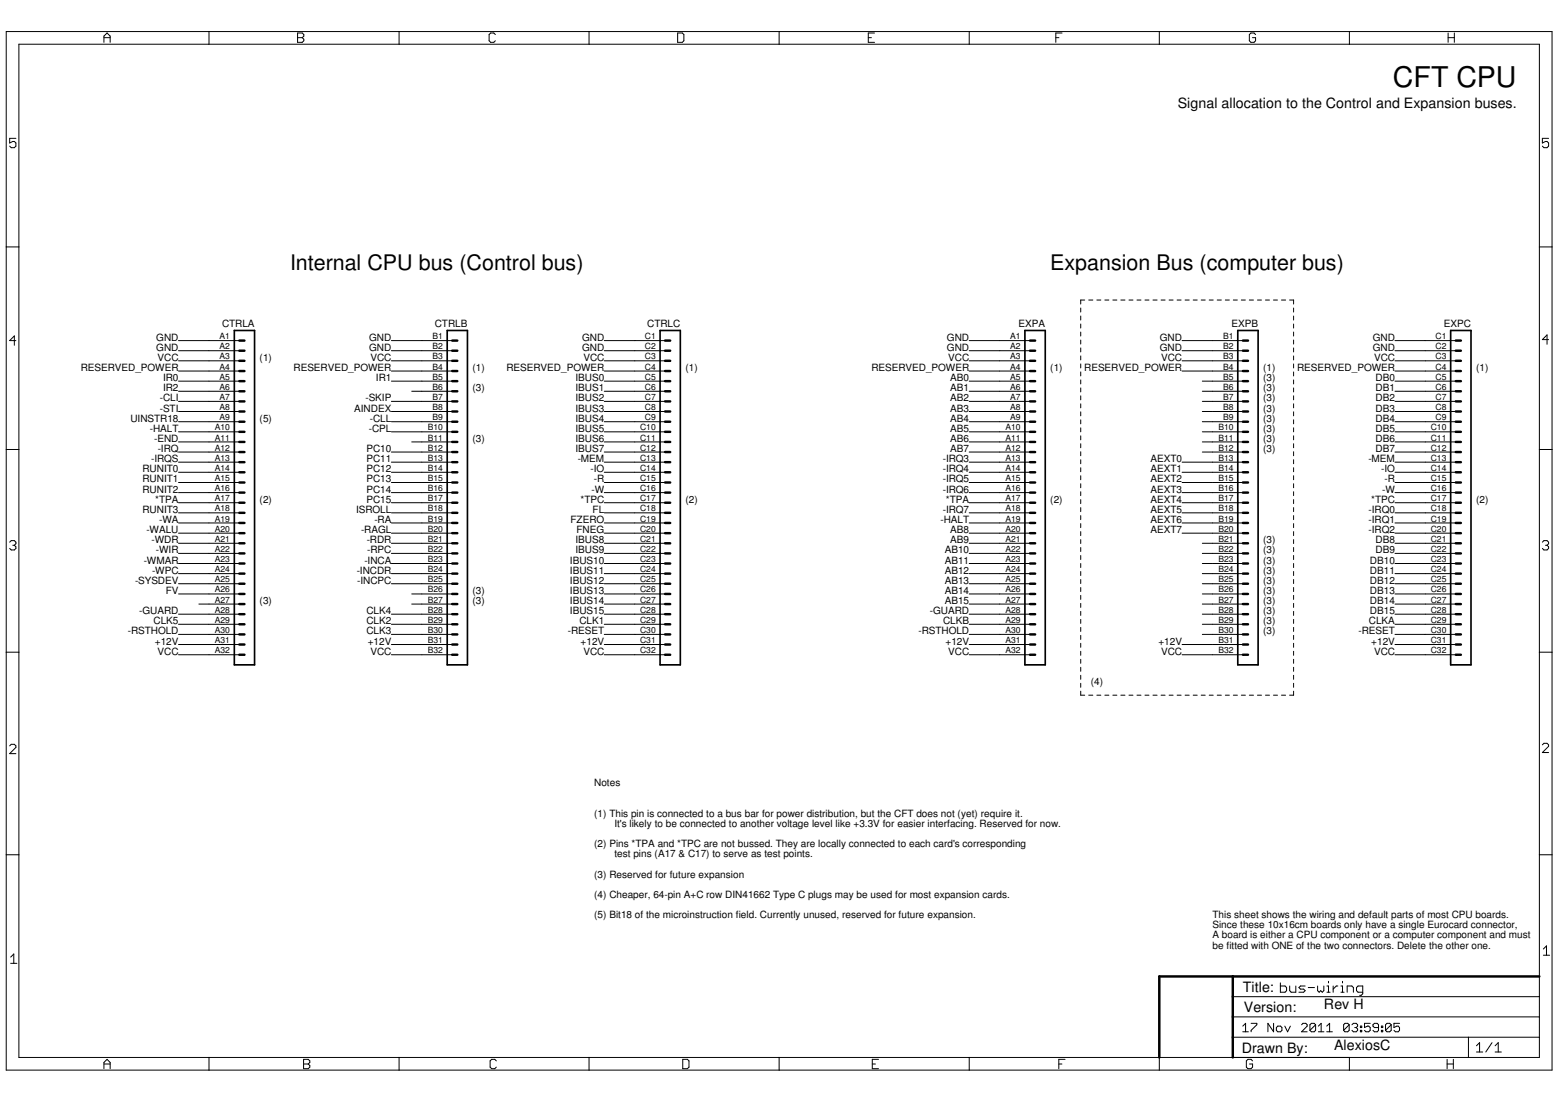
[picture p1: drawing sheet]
<svg xmlns="http://www.w3.org/2000/svg" width="297mm" height="210mm" viewBox="0 0 297 210" stroke-linecap="round" stroke-linejoin="round" font-family="sans-serif">
<defs><g id="words">
<text font-size="5.4" x="265.2" y="16.6">CFT CPU</text>
<g font-size="4.1">
<text x="55.2" y="51.4">Internal CPU bus (Control bus)</text>
<text x="200" y="51.4">Expansion Bus (computer bus)</text>
</g>
<g font-size="2.7">
<text x="224.3" y="20.5">Signal allocation to the Control and Expansion buses.</text>
<text x="236.7" y="189">Title:</text>
<text x="236.9" y="192.8">Version:</text>
<text x="252.1" y="192.3">Rev H</text>
<text x="236.5" y="200.6">Drawn By:</text>
<text x="254" y="200">AlexiosC</text>
</g>
<g font-size="1.9">
<text x="29.8" y="64.9">GND</text>
<text x="42.3" y="62.4">CTRLA</text>
<text x="70.3" y="64.9">GND</text>
<text x="82.8" y="62.4">CTRLB</text>
<text x="110.8" y="64.9">GND</text>
<text x="123.3" y="62.4">CTRLC</text>
<text x="180.3" y="64.9">GND</text>
<text x="193.9" y="62.4">EXPA</text>
<text x="220.8" y="64.9">GND</text>
<text x="234.5" y="62.4">EXPB</text>
<text x="261.4" y="64.9">GND</text>
<text x="274.9" y="62.4">EXPC</text>
<text x="15.4" y="70.7">RESERVED_POWER</text>
<text x="29.8" y="66.8">GND</text>
<text x="30" y="68.7">VCC</text>
<text x="49.4" y="68.7">(1)</text>
<text x="55.9" y="70.7">RESERVED_POWER</text>
<text x="70.3" y="66.8">GND</text>
<text x="70.6" y="68.7">VCC</text>
<text x="90" y="70.7">(1)</text>
<text x="96.4" y="70.7">RESERVED_POWER</text>
<text x="110.8" y="66.8">GND</text>
<text x="111.1" y="68.7">VCC</text>
<text x="130.5" y="70.7">(1)</text>
<text x="165.9" y="70.7">RESERVED_POWER</text>
<text x="180.3" y="66.8">GND</text>
<text x="180.6" y="68.7">VCC</text>
<text x="200" y="70.7">(1)</text>
<text x="206.5" y="70.7">RESERVED_POWER</text>
<text x="220.8" y="66.8">GND</text>
<text x="221.1" y="68.7">VCC</text>
<text x="240.5" y="70.7">(1)</text>
<text x="247" y="70.7">RESERVED_POWER</text>
<text x="261.4" y="66.8">GND</text>
<text x="261.6" y="68.7">VCC</text>
<text x="281.1" y="70.7">(1)</text>
<text x="30.4" y="76.5">-CLI</text>
<text x="31.1" y="72.6">IR0</text>
<text x="31.1" y="74.5">IR2</text>
<text x="69.6" y="76.5">-SKIP</text>
<text x="71.6" y="72.6">IR1</text>
<text x="90" y="74.5">(3)</text>
<text x="109.6" y="72.6">IBUS0</text>
<text x="109.6" y="74.5">IBUS1</text>
<text x="109.6" y="76.5">IBUS2</text>
<text x="180.9" y="76.5">AB2</text>
<text x="180.9" y="74.5">AB1</text>
<text x="180.9" y="72.6">AB0</text>
<text x="240.5" y="72.6">(3)</text>
<text x="240.5" y="74.5">(3)</text>
<text x="240.5" y="76.5">(3)</text>
<text x="261.9" y="76.5">DB2</text>
<text x="261.9" y="74.5">DB1</text>
<text x="261.9" y="72.6">DB0</text>
<text x="24.8" y="80.3">UINSTR18</text>
<text x="28.5" y="82.2">-HALT</text>
<text x="30.4" y="78.4">-STI</text>
<text x="49.4" y="80.3">(5)</text>
<text x="67.4" y="78.4">AINDEX</text>
<text x="70.2" y="82.2">-CPL</text>
<text x="70.4" y="80.3">-CLL</text>
<text x="109.6" y="78.4">IBUS3</text>
<text x="109.6" y="80.3">IBUS4</text>
<text x="109.6" y="82.2">IBUS5</text>
<text x="180.9" y="82.2">AB5</text>
<text x="180.9" y="80.3">AB4</text>
<text x="180.9" y="78.4">AB3</text>
<text x="240.5" y="78.4">(3)</text>
<text x="240.5" y="80.3">(3)</text>
<text x="240.5" y="82.2">(3)</text>
<text x="261.9" y="82.2">DB5</text>
<text x="261.9" y="80.3">DB4</text>
<text x="261.9" y="78.4">DB3</text>
<text x="27.1" y="90">RUNIT0</text>
<text x="28.8" y="88">-IRQS</text>
<text x="29.4" y="84.2">-END</text>
<text x="30" y="86.1">-IRQ</text>
<text x="69.8" y="86.1">PC10</text>
<text x="69.8" y="88">PC11</text>
<text x="69.8" y="90">PC12</text>
<text x="90" y="84.2">(3)</text>
<text x="109.6" y="84.2">IBUS6</text>
<text x="109.6" y="86.1">IBUS7</text>
<text x="110" y="88">-MEM</text>
<text x="112.5" y="90">-IO</text>
<text x="179.5" y="88">-IRQ3</text>
<text x="179.5" y="90">-IRQ4</text>
<text x="180.9" y="86.1">AB7</text>
<text x="180.9" y="84.2">AB6</text>
<text x="219" y="90">AEXT1</text>
<text x="219" y="88">AEXT0</text>
<text x="240.5" y="84.2">(3)</text>
<text x="240.5" y="86.1">(3)</text>
<text x="260.6" y="88">-MEM</text>
<text x="261.9" y="86.1">DB7</text>
<text x="261.9" y="84.2">DB6</text>
<text x="263" y="90">-IO</text>
<text x="27.1" y="91.9">RUNIT1</text>
<text x="27.1" y="93.8">RUNIT2</text>
<text x="29.6" y="95.8">*TPA</text>
<text x="49.4" y="95.8">(2)</text>
<text x="69.8" y="91.9">PC13</text>
<text x="69.8" y="93.8">PC14</text>
<text x="69.8" y="95.8">PC15</text>
<text x="110.5" y="95.8">*TPC</text>
<text x="112.7" y="93.8">-W</text>
<text x="113.1" y="91.9">-R</text>
<text x="130.5" y="95.8">(2)</text>
<text x="179.5" y="91.9">-IRQ5</text>
<text x="179.5" y="93.8">-IRQ6</text>
<text x="180.1" y="95.8">*TPA</text>
<text x="200" y="95.8">(2)</text>
<text x="219" y="95.8">AEXT4</text>
<text x="219" y="93.8">AEXT3</text>
<text x="219" y="91.9">AEXT2</text>
<text x="261.1" y="95.8">*TPC</text>
<text x="263.2" y="93.8">-W</text>
<text x="263.6" y="91.9">-R</text>
<text x="281.1" y="95.8">(2)</text>
<text x="27.1" y="97.7">RUNIT3</text>
<text x="27.9" y="101.5">-WALU</text>
<text x="30.3" y="99.6">-WA</text>
<text x="67.8" y="97.7">ISROLL</text>
<text x="68.8" y="101.5">-RAGL</text>
<text x="71.3" y="99.6">-RA</text>
<text x="108.6" y="99.6">FZERO</text>
<text x="109.8" y="101.5">FNEG</text>
<text x="112.8" y="97.7">FL</text>
<text x="179.1" y="99.6">-HALT</text>
<text x="179.5" y="97.7">-IRQ7</text>
<text x="180.9" y="101.5">AB8</text>
<text x="219" y="101.5">AEXT7</text>
<text x="219" y="99.6">AEXT6</text>
<text x="219" y="97.7">AEXT5</text>
<text x="260.6" y="97.7">-IRQ0</text>
<text x="260.6" y="101.5">-IRQ2</text>
<text x="260.6" y="99.6">-IRQ1</text>
<text x="27.4" y="107.3">-WMAR</text>
<text x="28.9" y="103.5">-WDR</text>
<text x="29.7" y="105.4">-WIR</text>
<text x="69.4" y="107.3">-INCA</text>
<text x="69.8" y="103.5">-RDR</text>
<text x="69.9" y="105.4">-RPC</text>
<text x="108.5" y="107.3">IBUS10</text>
<text x="109.6" y="105.4">IBUS9</text>
<text x="109.6" y="103.5">IBUS8</text>
<text x="179.9" y="107.3">AB11</text>
<text x="179.9" y="105.4">AB10</text>
<text x="180.9" y="103.5">AB9</text>
<text x="240.5" y="103.5">(3)</text>
<text x="240.5" y="105.4">(3)</text>
<text x="240.5" y="107.3">(3)</text>
<text x="260.8" y="107.3">DB10</text>
<text x="261.9" y="105.4">DB9</text>
<text x="261.9" y="103.5">DB8</text>
<text x="25.7" y="111.2">-SYSDEV</text>
<text x="29" y="109.3">-WPC</text>
<text x="31.6" y="113.1">FV</text>
<text x="67.9" y="109.3">-INCDR</text>
<text x="68" y="111.2">-INCPC</text>
<text x="90" y="113.1">(3)</text>
<text x="108.5" y="113.1">IBUS13</text>
<text x="108.5" y="111.2">IBUS12</text>
<text x="108.5" y="109.3">IBUS11</text>
<text x="179.9" y="113.1">AB14</text>
<text x="179.9" y="111.2">AB13</text>
<text x="179.9" y="109.3">AB12</text>
<text x="240.5" y="109.3">(3)</text>
<text x="240.5" y="111.2">(3)</text>
<text x="240.5" y="113.1">(3)</text>
<text x="260.8" y="113.1">DB13</text>
<text x="260.8" y="111.2">DB12</text>
<text x="260.8" y="109.3">DB11</text>
<text x="26.5" y="117">-GUARD</text>
<text x="29.3" y="118.9">CLK5</text>
<text x="49.4" y="115.1">(3)</text>
<text x="69.8" y="118.9">CLK2</text>
<text x="69.8" y="117">CLK4</text>
<text x="90" y="115.1">(3)</text>
<text x="108.5" y="117">IBUS15</text>
<text x="108.5" y="115.1">IBUS14</text>
<text x="110.3" y="118.9">CLK1</text>
<text x="177.1" y="117">-GUARD</text>
<text x="179.6" y="118.9">CLKB</text>
<text x="179.9" y="115.1">AB15</text>
<text x="240.5" y="115.1">(3)</text>
<text x="240.5" y="117">(3)</text>
<text x="240.5" y="118.9">(3)</text>
<text x="260.7" y="118.9">CLKA</text>
<text x="260.8" y="117">DB15</text>
<text x="260.8" y="115.1">DB14</text>
<text x="24.4" y="120.8">-RSTHOLD</text>
<text x="29.5" y="122.8">+12V</text>
<text x="30" y="124.7">VCC</text>
<text x="69.8" y="120.8">CLK3</text>
<text x="70" y="122.8">+12V</text>
<text x="70.6" y="124.7">VCC</text>
<text x="108.1" y="120.8">-RESET</text>
<text x="110.6" y="122.8">+12V</text>
<text x="111.1" y="124.7">VCC</text>
<text x="174.9" y="120.8">-RSTHOLD</text>
<text x="180" y="122.8">+12V</text>
<text x="180.6" y="124.7">VCC</text>
<text x="220.6" y="122.8">+12V</text>
<text x="221.1" y="124.7">VCC</text>
<text x="240.5" y="120.8">(3)</text>
<text x="258.7" y="120.8">-RESET</text>
<text x="261.1" y="122.8">+12V</text>
<text x="261.6" y="124.7">VCC</text>
<text x="207.7" y="130.5">(4)</text>
<text x="113.1" y="149.8">Notes</text>
<text x="113.1" y="155.6">(1) This pin is connected to a bus bar for power distribution, but the CFT does not (yet) require it.</text>
<text x="113.1" y="161.4">(2) Pins *TPA and *TPC are not bussed. They are locally connected to each card's corresponding</text>
<text x="117" y="157.5">It's likely to be connected to another voltage level like +3.3V for easier interfacing. Reserved for now.</text>
<text x="113.1" y="167.2">(3) Reserved for future expansion</text>
<text x="117" y="163.3">test pins (A17 &amp; C17) to serve as test points.</text>
<text x="113.1" y="171">(4) Cheaper, 64-pin A+C row DIN41662 Type C plugs may be used for most expansion cards.</text>
<text x="113.1" y="174.9">(5) Bit18 of the microinstruction field. Currently unused, reserved for future expansion.</text>
<text x="230.9" y="174.9">This sheet shows the wiring and default parts of most CPU boards.</text>
<text x="230.9" y="176.8">Since these 10x16cm boards only have a single Eurocard connector,</text>
<text x="230.9" y="178.7">A board is either a CPU component or a computer component and must</text>
<text x="230.9" y="180.7">be fitted with ONE of the two connectors. Delete the other one.</text>
</g>
<g font-size="1.6">
<text x="41.8" y="64.6">A1</text>
<text x="82.3" y="64.6">B1</text>
<text x="122.8" y="64.6">C1</text>
<text x="192.4" y="64.6">A1</text>
<text x="232.9" y="64.6">B1</text>
<text x="273.3" y="64.6">C1</text>
<text x="41.8" y="66.5">A2</text>
<text x="41.8" y="68.5">A3</text>
<text x="41.8" y="70.4">A4</text>
<text x="82.3" y="66.5">B2</text>
<text x="82.3" y="68.5">B3</text>
<text x="82.3" y="70.4">B4</text>
<text x="122.8" y="66.5">C2</text>
<text x="122.8" y="68.5">C3</text>
<text x="122.8" y="70.4">C4</text>
<text x="192.4" y="66.5">A2</text>
<text x="192.4" y="68.5">A3</text>
<text x="192.4" y="70.4">A4</text>
<text x="232.9" y="66.5">B2</text>
<text x="232.9" y="68.5">B3</text>
<text x="232.9" y="70.4">B4</text>
<text x="273.3" y="66.5">C2</text>
<text x="273.3" y="68.5">C3</text>
<text x="273.3" y="70.4">C4</text>
<text x="41.8" y="72.3">A5</text>
<text x="41.8" y="74.3">A6</text>
<text x="41.8" y="76.2">A7</text>
<text x="82.3" y="72.3">B5</text>
<text x="82.3" y="74.3">B6</text>
<text x="82.3" y="76.2">B7</text>
<text x="122.8" y="72.3">C5</text>
<text x="122.8" y="74.3">C6</text>
<text x="122.8" y="76.2">C7</text>
<text x="192.4" y="72.3">A5</text>
<text x="192.4" y="74.3">A6</text>
<text x="192.4" y="76.2">A7</text>
<text x="232.9" y="72.3">B5</text>
<text x="232.9" y="74.3">B6</text>
<text x="232.9" y="76.2">B7</text>
<text x="273.3" y="72.3">C5</text>
<text x="273.3" y="74.3">C6</text>
<text x="273.3" y="76.2">C7</text>
<text x="40.9" y="82">A10</text>
<text x="40.9" y="83.9">A11</text>
<text x="41.8" y="78.1">A8</text>
<text x="41.8" y="80">A9</text>
<text x="81.4" y="82">B10</text>
<text x="81.4" y="83.9">B11</text>
<text x="82.3" y="78.1">B8</text>
<text x="82.3" y="80">B9</text>
<text x="121.9" y="82">C10</text>
<text x="121.9" y="83.9">C11</text>
<text x="122.8" y="78.1">C8</text>
<text x="122.8" y="80">C9</text>
<text x="191.5" y="82">A10</text>
<text x="191.5" y="83.9">A11</text>
<text x="192.4" y="78.1">A8</text>
<text x="192.4" y="80">A9</text>
<text x="232" y="82">B10</text>
<text x="232" y="83.9">B11</text>
<text x="232.9" y="78.1">B8</text>
<text x="232.9" y="80">B9</text>
<text x="272.4" y="82">C10</text>
<text x="272.4" y="83.9">C11</text>
<text x="273.3" y="78.1">C8</text>
<text x="273.3" y="80">C9</text>
<text x="40.9" y="85.8">A12</text>
<text x="40.9" y="87.8">A13</text>
<text x="40.9" y="89.7">A14</text>
<text x="81.4" y="85.8">B12</text>
<text x="81.4" y="87.8">B13</text>
<text x="81.4" y="89.7">B14</text>
<text x="121.9" y="85.8">C12</text>
<text x="121.9" y="87.8">C13</text>
<text x="121.9" y="89.7">C14</text>
<text x="191.5" y="85.8">A12</text>
<text x="191.5" y="87.8">A13</text>
<text x="191.5" y="89.7">A14</text>
<text x="232" y="85.8">B12</text>
<text x="232" y="87.8">B13</text>
<text x="232" y="89.7">B14</text>
<text x="272.4" y="85.8">C12</text>
<text x="272.4" y="87.8">C13</text>
<text x="272.4" y="89.7">C14</text>
<text x="40.9" y="91.6">A15</text>
<text x="40.9" y="93.6">A16</text>
<text x="40.9" y="95.5">A17</text>
<text x="81.4" y="91.6">B15</text>
<text x="81.4" y="93.6">B16</text>
<text x="81.4" y="95.5">B17</text>
<text x="121.9" y="91.6">C15</text>
<text x="121.9" y="93.6">C16</text>
<text x="121.9" y="95.5">C17</text>
<text x="191.5" y="91.6">A15</text>
<text x="191.5" y="93.6">A16</text>
<text x="191.5" y="95.5">A17</text>
<text x="232" y="91.6">B15</text>
<text x="232" y="93.6">B16</text>
<text x="232" y="95.5">B17</text>
<text x="272.4" y="91.6">C15</text>
<text x="272.4" y="93.6">C16</text>
<text x="272.4" y="95.5">C17</text>
<text x="40.9" y="97.4">A18</text>
<text x="40.9" y="99.3">A19</text>
<text x="40.9" y="101.3">A20</text>
<text x="81.4" y="97.4">B18</text>
<text x="81.4" y="99.3">B19</text>
<text x="81.4" y="101.3">B20</text>
<text x="121.9" y="97.4">C18</text>
<text x="121.9" y="99.3">C19</text>
<text x="121.9" y="101.3">C20</text>
<text x="191.5" y="97.4">A18</text>
<text x="191.5" y="99.3">A19</text>
<text x="191.5" y="101.3">A20</text>
<text x="232" y="97.4">B18</text>
<text x="232" y="99.3">B19</text>
<text x="232" y="101.3">B20</text>
<text x="272.4" y="97.4">C18</text>
<text x="272.4" y="99.3">C19</text>
<text x="272.4" y="101.3">C20</text>
<text x="40.9" y="103.2">A21</text>
<text x="40.9" y="105.1">A22</text>
<text x="40.9" y="107.1">A23</text>
<text x="81.4" y="103.2">B21</text>
<text x="81.4" y="105.1">B22</text>
<text x="81.4" y="107.1">B23</text>
<text x="121.9" y="103.2">C21</text>
<text x="121.9" y="105.1">C22</text>
<text x="121.9" y="107.1">C23</text>
<text x="191.5" y="103.2">A21</text>
<text x="191.5" y="105.1">A22</text>
<text x="191.5" y="107.1">A23</text>
<text x="232" y="103.2">B21</text>
<text x="232" y="105.1">B22</text>
<text x="232" y="107.1">B23</text>
<text x="272.4" y="103.2">C21</text>
<text x="272.4" y="105.1">C22</text>
<text x="272.4" y="107.1">C23</text>
<text x="40.9" y="109">A24</text>
<text x="40.9" y="110.9">A25</text>
<text x="40.9" y="112.9">A26</text>
<text x="81.4" y="109">B24</text>
<text x="81.4" y="110.9">B25</text>
<text x="81.4" y="112.9">B26</text>
<text x="121.9" y="109">C24</text>
<text x="121.9" y="110.9">C25</text>
<text x="121.9" y="112.9">C26</text>
<text x="191.5" y="109">A24</text>
<text x="191.5" y="110.9">A25</text>
<text x="191.5" y="112.9">A26</text>
<text x="232" y="109">B24</text>
<text x="232" y="110.9">B25</text>
<text x="232" y="112.9">B26</text>
<text x="272.4" y="109">C24</text>
<text x="272.4" y="110.9">C25</text>
<text x="272.4" y="112.9">C26</text>
<text x="40.9" y="114.8">A27</text>
<text x="40.9" y="116.7">A28</text>
<text x="40.9" y="118.6">A29</text>
<text x="81.4" y="114.8">B27</text>
<text x="81.4" y="116.7">B28</text>
<text x="81.4" y="118.6">B29</text>
<text x="121.9" y="114.8">C27</text>
<text x="121.9" y="116.7">C28</text>
<text x="121.9" y="118.6">C29</text>
<text x="191.5" y="114.8">A27</text>
<text x="191.5" y="116.7">A28</text>
<text x="191.5" y="118.6">A29</text>
<text x="232" y="114.8">B27</text>
<text x="232" y="116.7">B28</text>
<text x="232" y="118.6">B29</text>
<text x="272.4" y="114.8">C27</text>
<text x="272.4" y="116.7">C28</text>
<text x="272.4" y="118.6">C29</text>
<text x="40.9" y="120.6">A30</text>
<text x="40.9" y="122.5">A31</text>
<text x="40.9" y="124.4">A32</text>
<text x="81.4" y="120.6">B30</text>
<text x="81.4" y="122.5">B31</text>
<text x="81.4" y="124.4">B32</text>
<text x="121.9" y="120.6">C30</text>
<text x="121.9" y="122.5">C31</text>
<text x="121.9" y="124.4">C32</text>
<text x="191.5" y="120.6">A30</text>
<text x="191.5" y="122.5">A31</text>
<text x="191.5" y="124.4">A32</text>
<text x="232" y="120.6">B30</text>
<text x="232" y="122.5">B31</text>
<text x="232" y="124.4">B32</text>
<text x="272.4" y="120.6">C30</text>
<text x="272.4" y="122.5">C31</text>
<text x="272.4" y="124.4">C32</text>
</g>
</g></defs>
<g fill="#000" stroke="#000" stroke-width=".19">
<path d="M1.2 6v41zM3.6 8.4v38.6zM19.8 6.9v1.2zM19.8 6.9l.6-.6zM19.8 7.2h1.2zM20.4 6.3l.6 .6zM21 6.9v1.2zM1.2 6h38.6zM3.6 8.4h36.2zM39.8 6v2.4zM56.7 6.3v1.8zM56.7 6.3h.9z"/>
<path d="M56.7 7.2h.9zM57.6 6.3l.2 .3zM57.6 7.2l.2 .3zM56.7 8.1h.9zM57.8 6.6v.3zM57.8 6.9l-.2 .3zM57.8 7.5v.3zM57.8 7.8l-.2 .3zM39.8 6h36.2zM39.8 8.4h36.2zM76 6v2.4zM93.1 6.6v1.2z"/>
<path d="M93.1 7.8l.3 .3zM93.4 6.3l-.3 .3zM93.4 8.1h.6zM93.4 6.3h.6zM94 8.1l.3-.3zM94 6.3l.3 .3zM76 6h36.2zM76 8.4h36.2zM112.2 6v2.4zM129 6.3v1.8zM129 8.1h.9zM129.9 8.1l.3-.3z"/>
<path d="M129 6.3h.9zM130.2 6.6v1.2zM129.9 6.3l.3 .3zM112.2 8.4h36.2zM112.2 6h36.2zM148.4 6v2.4zM165.3 6.3v1.8zM165.3 8.1h1.2zM165.3 7.2h.6zM165.3 6.3h1.2zM148.4 8.4h36.1zM148.4 6h36.1z"/>
<path d="M184.5 6v2.4zM201 6.3v1.8zM201 6.3h1.2zM201 7.2h.6zM184.5 8.4h36.2zM184.5 6h36.2zM220.7 6v2.4zM237.9 6.6v1.2zM237.9 7.8l.3 .3zM238.2 6.3l-.3 .3zM238.2 8.1h.6zM238.2 6.3h.6z"/>
<path d="M238.8 8.1l.3-.3zM238.8 6.3l.3 .3zM239.1 7.2v.6zM238.5 7.2h.6zM220.7 8.4h36.2zM220.7 6h36.2zM256.9 6v2.4zM275.7 6.3v1.8zM275.7 7.2h1.2zM276.9 6.3v1.8zM256.9 8.4h36.2zM256.9 6h38.6z"/>
<path d="M1.8 26.4v.8zM1.8 27.2l.6-.3zM1.8 27.8l.3 .3zM2.4 26.9h.3zM2.7 26.9l.3 .3zM2.1 28.1h.6zM1.8 26.4h1.2zM3 27.2v.6zM3 27.8l-.3 .3zM293.7 26.4v.8zM293.7 27.2l.6-.3zM293.7 27.8l.3 .3z"/>
<path d="M294.3 26.9h.3zM294.6 26.9l.3 .3zM294 28.1h.6zM293.7 26.4h1.2zM294.9 27.2v.6zM294.9 27.8l-.3 .3zM1.2 47v38.6zM1.2 47h2.4zM3.6 47v38.6zM205.8 57.1v.8zM205.8 58.7v.7zM205.8 57.1h.7z"/>
<path d="M207.3 57.1h.8zM208.8 57.1h.8zM210.4 57.1h.7zM211.9 57.1h.8zM213.4 57.1h.8zM215 57.1h.7zM216.5 57.1h.8zM218 57.1h.8zM219.5 57.1h.8zM221.1 57.1h.7zM222.6 57.1h.8zM224.1 57.1h.8z"/>
<path d="M225.7 57.1h.7zM227.2 57.1h.8zM228.7 57.1h.8zM230.2 57.1h.8zM231.8 57.1h.8zM233.3 57.1h.8zM234.8 57.1h.8zM236.4 57.1h.7zM237.9 57.1h.8zM239.4 57.1h.8zM241 57.1h.7zM242.5 57.1h.7z"/>
<path d="M244 57.1h.8zM246.3 58.7v.7zM246.3 57.1v.8zM245.6 57.1h.7zM293.1 8.4v38.6zM293.1 47h2.4zM295.5 6v41zM1.8 64.9h1.2zM2.7 64v1.8zM2.7 64l-.9 .9zM34 78.4h5.8zM34 76.5h5.8z"/>
<path d="M39.8 64.9h5.8zM39.8 66.8h5.8zM39.8 68.7h5.8zM39.8 70.7h5.8zM39.8 72.6h5.8zM39.8 74.5h5.8zM39.8 76.5h5.8zM39.8 78.4h5.8zM34 66.8h5.8zM34 64.9h5.8zM34 68.7h5.8zM34 70.7h5.8z"/>
<path d="M34 72.6h5.8zM34 74.5h5.8zM74.5 78.4h5.8zM74.5 76.5h5.8zM80.3 64.9h5.8zM80.3 66.8h5.8zM80.3 68.7h5.8zM80.3 70.7h5.8zM80.3 72.6h5.8zM80.3 74.5h5.8zM80.3 76.5h5.8zM80.3 78.4h5.8z"/>
<path d="M74.5 66.8h5.8zM74.5 64.9h5.8zM74.5 68.7h5.8zM74.5 70.7h5.8zM74.5 72.6h5.8zM78.4 74.5h1.9zM120.9 64.9h5.7zM120.9 66.8h5.7zM120.9 68.7h5.7zM120.9 70.7h5.7zM120.9 72.6h5.7zM120.9 74.5h5.7z"/>
<path d="M120.9 76.5h5.7zM120.9 78.4h5.7zM115.1 66.8h5.8zM115.1 64.9h5.8zM115.1 68.7h5.8zM115.1 70.7h5.8zM115.1 72.6h5.8zM115.1 74.5h5.8zM115.1 76.5h5.8zM115.1 78.4h5.8zM184.5 78.4h5.8zM184.5 76.5h5.8z"/>
<path d="M184.5 74.5h5.8zM184.5 72.6h5.8zM190.3 64.9h5.8zM190.3 66.8h5.8zM190.3 68.7h5.8zM190.3 70.7h5.8zM190.3 72.6h5.8zM190.3 74.5h5.8zM190.3 76.5h5.8zM190.3 78.4h5.8zM184.5 66.8h5.8zM184.5 64.9h5.8z"/>
<path d="M184.5 68.7h5.8zM184.5 70.7h5.8zM205.8 60.2v.8zM205.8 61.7v.8zM205.8 63.2v.8zM205.8 64.8v.7zM205.8 66.3v.7zM205.8 67.8v.8zM205.8 69.3v.8zM205.8 70.8v.8zM205.8 72.4v.7zM205.8 73.9v.8z"/>
<path d="M205.8 75.4v.8zM205.8 76.9v.8zM205.8 78.4v.8zM205.8 80v.7zM228.9 78.4h2zM228.9 76.5h2zM228.9 74.5h2zM228.9 72.6h2zM230.9 64.9h5.8zM230.9 66.8h5.8zM230.9 68.7h5.8zM230.9 70.7h5.8z"/>
<path d="M230.9 72.6h5.8zM230.9 74.5h5.8zM230.9 76.5h5.8zM230.9 78.4h5.8zM225.1 66.8h5.8zM225.1 64.9h5.8zM225.1 68.7h5.8zM225.1 70.7h5.8zM246.3 78.4v.8zM246.3 76.9v.8zM246.3 75.4v.8zM246.3 73.9v.8z"/>
<path d="M246.3 72.4v.7zM246.3 70.8v.8zM246.3 69.3v.8zM246.3 67.8v.8zM246.3 66.3v.7zM246.3 64.8v.7zM246.3 63.2v.8zM246.3 61.7v.8zM246.3 60.2v.8zM265.6 78.4h5.8zM265.6 76.5h5.8zM265.6 74.5h5.8z"/>
<path d="M265.6 72.6h5.8zM271.4 64.9h5.8zM271.4 66.8h5.8zM271.4 68.7h5.8zM271.4 70.7h5.8zM271.4 72.6h5.8zM271.4 74.5h5.8zM271.4 76.5h5.8zM271.4 78.4h5.8zM265.6 66.8h5.8zM265.6 64.9h5.8zM265.6 68.7h5.8z"/>
<path d="M265.6 70.7h5.8zM293.7 64.7h1.2zM294.6 63.8v1.8zM294.6 63.8l-.9 .9zM1.2 85.6v38.6zM1.2 85.6h2.4zM3.6 85.6v38.6zM34 88h5.8zM34 86.1h5.8zM34 99.6h5.8zM34 97.7h5.8zM34 91.9h5.8z"/>
<path d="M34 90h5.8zM34 80.3h5.8zM39.8 80.3h5.8zM39.8 82.3h5.8zM39.8 84.2h5.8zM39.8 86.1h5.8zM39.8 88h5.8zM39.8 90h5.8zM39.8 91.9h5.8zM39.8 93.8h5.8zM39.8 95.8h5.8zM39.8 97.7h5.8z"/>
<path d="M39.8 99.6h5.8zM34 95.8h5.8zM34 82.3h5.8zM34 93.8h5.8zM34 84.2h5.8zM74.5 99.6h5.8zM74.5 97.7h5.8zM74.5 82.3h5.8zM74.5 80.3h5.8zM80.3 80.3h5.8zM80.3 82.3h5.8zM80.3 84.2h5.8z"/>
<path d="M80.3 86.1h5.8zM80.3 88h5.8zM80.3 90h5.8zM80.3 91.9h5.8zM80.3 93.8h5.8zM80.3 95.8h5.8zM80.3 97.7h5.8zM80.3 99.6h5.8zM74.5 86.1h5.8zM74.5 88h5.8zM74.5 90h5.8zM74.5 91.9h5.8z"/>
<path d="M74.5 93.8h5.8zM74.5 95.8h5.8zM78.4 84.2h1.9zM120.9 80.3h5.7zM120.9 82.3h5.7zM120.9 84.2h5.7zM120.9 86.1h5.7zM120.9 88h5.7zM120.9 90h5.7zM120.9 91.9h5.7zM120.9 93.8h5.7zM120.9 95.8h5.7z"/>
<path d="M120.9 97.7h5.7zM120.9 99.6h5.7zM115.1 95.8h5.8zM115.1 80.3h5.8zM115.1 82.3h5.8zM115.1 84.2h5.8zM115.1 86.1h5.8zM115.1 88h5.8zM115.1 90h5.8zM115.1 91.9h5.8zM115.1 93.8h5.8zM115.1 97.7h5.8z"/>
<path d="M115.1 99.6h5.8zM184.5 86.1h5.8zM184.5 84.2h5.8zM184.5 82.3h5.8zM184.5 80.3h5.8zM190.3 80.3h5.8zM190.3 82.3h5.8zM190.3 84.2h5.8zM190.3 86.1h5.8zM190.3 88h5.8zM190.3 90h5.8zM190.3 91.9h5.8z"/>
<path d="M190.3 93.8h5.8zM190.3 95.8h5.8zM190.3 97.7h5.8zM190.3 99.6h5.8zM184.5 95.8h5.8zM184.5 99.6h5.8zM184.5 88h5.8zM184.5 90h5.8zM184.5 91.9h5.8zM184.5 97.7h5.8zM184.5 93.8h5.8zM205.8 81.5v.8z"/>
<path d="M205.8 83v.8zM205.8 84.5v.8zM205.8 86v.8zM205.8 87.6v.7zM205.8 89.1v.8zM205.8 90.6v.8zM205.8 92.1v.8zM205.8 93.7v.7zM205.8 95.2v.7zM205.8 96.7v.7zM205.8 98.2v.8zM205.8 99.7v.8z"/>
<path d="M225.1 99.6h5.8zM225.1 97.7h5.8zM225.1 95.8h5.8zM225.1 93.8h5.8zM225.1 91.9h5.8zM225.1 90h5.8zM225.1 88h5.8zM228.9 86.1h2zM228.9 84.2h2zM228.9 82.3h2zM228.9 80.3h2zM230.9 80.3h5.8z"/>
<path d="M230.9 82.3h5.8zM230.9 84.2h5.8zM230.9 86.1h5.8zM230.9 88h5.8zM230.9 90h5.8zM230.9 91.9h5.8zM230.9 93.8h5.8zM230.9 95.8h5.8zM230.9 97.7h5.8zM230.9 99.6h5.8zM246.3 98.2v.8zM246.3 96.7v.7z"/>
<path d="M246.3 95.2v.7zM246.3 93.7v.7zM246.3 92.1v.8zM246.3 90.6v.8zM246.3 89.1v.8zM246.3 87.6v.7zM246.3 86v.8zM246.3 84.5v.8zM246.3 83v.8zM246.3 81.5v.8zM246.3 80v.7zM265.6 86.1h5.8z"/>
<path d="M265.6 84.2h5.8zM265.6 82.3h5.8zM265.6 80.3h5.8zM271.4 80.3h5.8zM271.4 82.3h5.8zM271.4 84.2h5.8zM271.4 86.1h5.8zM271.4 88h5.8zM271.4 90h5.8zM271.4 91.9h5.8zM271.4 93.8h5.8zM271.4 95.8h5.8z"/>
<path d="M271.4 97.7h5.8zM271.4 99.6h5.8zM265.6 95.8h5.8zM265.6 88h5.8zM265.6 90h5.8zM265.6 91.9h5.8zM265.6 93.8h5.8zM265.6 97.7h5.8zM265.6 99.6h5.8zM293.1 47v38.6zM293.1 85.6h2.4zM295.5 47v38.6z"/>
<path d="M1.8 103.3l.3-.3zM2.1 103h.6zM1.8 104.5l.3 .3zM2.7 103l.3 .3zM2.4 103.9h.3zM2.7 103.9l.3 .3zM2.1 104.8h.6zM3 103.3v.3zM3 103.6l-.3 .3zM3 104.2v.3zM3 104.5l-.3 .3zM34 107.3h5.8z"/>
<path d="M34 105.4h5.8zM34 103.5h5.8zM34 101.6h5.8zM34 109.3h5.8zM34 117h5.8zM39.8 101.6h5.8zM39.8 103.5h5.8zM39.8 105.4h5.8zM39.8 107.3h5.8zM39.8 109.3h5.8zM39.8 111.2h5.8zM39.8 113.1h5.8z"/>
<path d="M39.8 115.1h5.8zM39.8 117h5.8zM39.8 118.9h5.8zM34 111.2h5.8zM34 118.9h5.8zM34 113.1h5.8zM37.9 115.1h1.9zM74.5 107.3h5.8zM74.5 105.4h5.8zM74.5 103.5h5.8zM74.5 101.6h5.8zM74.5 118.9h5.8z"/>
<path d="M74.5 111.2h5.8zM74.5 109.3h5.8zM80.3 101.6h5.8zM80.3 103.5h5.8zM80.3 105.4h5.8zM80.3 107.3h5.8zM80.3 109.3h5.8zM80.3 111.2h5.8zM80.3 113.1h5.8zM80.3 115.1h5.8zM80.3 117h5.8zM80.3 118.9h5.8z"/>
<path d="M74.5 117h5.8zM78.4 115.1h1.9zM78.4 113.1h1.9zM115.1 117h5.8zM115.1 115.1h5.8zM115.1 113.1h5.8zM115.1 111.2h5.8zM115.1 107.3h5.8zM115.1 105.4h5.8zM115.1 103.5h5.8zM115.1 101.6h5.8zM115.1 118.9h5.8z"/>
<path d="M120.9 101.6h5.7zM120.9 103.5h5.7zM120.9 105.4h5.7zM120.9 107.3h5.7zM120.9 109.3h5.7zM120.9 111.2h5.7zM120.9 113.1h5.7zM120.9 115.1h5.7zM120.9 117h5.7zM120.9 118.9h5.7zM115.1 109.3h5.8zM184.5 115.1h5.8z"/>
<path d="M184.5 113.1h5.8zM184.5 111.2h5.8zM184.5 109.3h5.8zM184.5 107.3h5.8zM184.5 105.4h5.8zM184.5 103.5h5.8zM184.5 101.6h5.8zM184.5 117h5.8zM190.3 101.6h5.8zM190.3 103.5h5.8zM190.3 105.4h5.8zM190.3 107.3h5.8z"/>
<path d="M190.3 109.3h5.8zM190.3 111.2h5.8zM190.3 113.1h5.8zM190.3 115.1h5.8zM190.3 117h5.8zM190.3 118.9h5.8zM184.5 118.9h5.8zM205.8 101.3v.7zM205.8 102.8v.7zM205.8 104.3v.7zM205.8 105.8v.8zM205.8 107.3v.8z"/>
<path d="M205.8 108.9v.7zM205.8 110.4v.7zM205.8 111.9v.8zM205.8 113.4v.8zM205.8 114.9v.8zM205.8 116.5v.7zM205.8 118v.7zM205.8 119.5v.8zM225.1 101.6h5.8zM228.9 117h2zM228.9 115.1h2zM228.9 113.1h2z"/>
<path d="M228.9 111.2h2zM228.9 109.3h2zM228.9 107.3h2zM228.9 105.4h2zM228.9 103.5h2zM230.9 101.6h5.8zM230.9 103.5h5.8zM230.9 105.4h5.8zM230.9 107.3h5.8zM230.9 109.3h5.8zM230.9 111.2h5.8zM230.9 113.1h5.8z"/>
<path d="M230.9 115.1h5.8zM230.9 117h5.8zM230.9 118.9h5.8zM228.9 118.9h2zM246.3 118v.7zM246.3 116.5v.7zM246.3 114.9v.8zM246.3 113.4v.8zM246.3 111.9v.8zM246.3 110.4v.7zM246.3 108.9v.7zM246.3 107.3v.8z"/>
<path d="M246.3 105.8v.8zM246.3 104.3v.7zM246.3 102.8v.7zM246.3 101.3v.7zM246.3 99.7v.8zM265.6 117h5.8zM265.6 115.1h5.8zM265.6 113.1h5.8zM265.6 111.2h5.8zM265.6 109.3h5.8zM265.6 107.3h5.8zM265.6 105.4h5.8z"/>
<path d="M265.6 103.5h5.8zM265.6 118.9h5.8zM271.4 101.6h5.8zM271.4 103.5h5.8zM271.4 105.4h5.8zM271.4 107.3h5.8zM271.4 109.3h5.8zM271.4 111.2h5.8zM271.4 113.1h5.8zM271.4 115.1h5.8zM271.4 117h5.8zM271.4 118.9h5.8z"/>
<path d="M265.6 101.6h5.8zM293.7 103.3l.3-.3zM294 103h.6zM293.7 104.5l.3 .3zM294.6 103l.3 .3zM294.3 103.9h.3zM294.6 103.9l.3 .3zM294 104.8h.6zM294.9 103.3v.3zM294.9 103.6l-.3 .3zM294.9 104.2v.3zM294.9 104.5l-.3 .3z"/>
<path d="M1.2 124.2v38.6zM1.2 124.2h2.4zM3.6 124.2v38.6zM39.8 120.8h5.8zM39.8 122.8h5.8zM39.8 124.7h5.8zM34 124.7h5.8zM34 122.8h5.8zM34 120.8h5.8zM80.3 120.8h5.8zM80.3 122.8h5.8zM80.3 124.7h5.8z"/>
<path d="M74.5 124.7h5.8zM74.5 122.8h5.8zM74.5 120.8h5.8zM120.9 120.8h5.7zM120.9 122.8h5.7zM120.9 124.7h5.7zM115.1 124.7h5.8zM115.1 122.8h5.8zM115.1 120.8h5.8zM190.3 120.8h5.8zM190.3 122.8h5.8zM190.3 124.7h5.8z"/>
<path d="M184.5 124.7h5.8zM184.5 122.8h5.8zM184.5 120.8h5.8zM205.8 121v.8zM205.8 122.5v.8zM205.8 124.1v.7zM205.8 125.6v.7zM205.8 127.1v.8zM205.8 128.6v.8zM205.8 130.2v.7zM205.8 131.7v.7zM205.8 132.4h.7z"/>
<path d="M207.3 132.4h.8zM208.8 132.4h.8zM210.4 132.4h.7zM211.9 132.4h.8zM213.4 132.4h.8zM215 132.4h.7zM216.5 132.4h.8zM218 132.4h.8zM219.5 132.4h.8zM221.1 132.4h.7zM222.6 132.4h.8zM224.1 132.4h.8z"/>
<path d="M225.7 132.4h.7zM227.2 132.4h.8zM228.7 132.4h.8zM230.2 132.4h.8zM230.9 120.8h5.8zM230.9 122.8h5.8zM230.9 124.7h5.8zM225.1 124.7h5.8zM225.1 122.8h5.8zM228.9 120.8h2zM231.8 132.4h.8zM233.3 132.4h.8z"/>
<path d="M234.8 132.4h.8zM236.4 132.4h.7zM237.9 132.4h.8zM239.4 132.4h.8zM241 132.4h.7zM242.5 132.4h.7zM244 132.4h.8zM245.6 132.4h.7zM246.3 131.7v.7zM246.3 130.2v.7zM246.3 128.6v.8zM246.3 127.1v.8z"/>
<path d="M246.3 125.6v.7zM246.3 124.1v.7zM246.3 122.5v.8zM246.3 121v.8zM246.3 119.5v.8zM271.4 120.8h5.8zM271.4 122.8h5.8zM271.4 124.7h5.8zM265.6 124.7h5.8zM265.6 122.8h5.8zM265.6 120.8h5.8zM293.1 85.6v38.6z"/>
<path d="M293.1 124.2h2.4zM295.5 85.6v38.6zM1.8 143.5l1.2-1.1zM2.1 141.8l-.3 .3zM2.1 141.8h.6zM1.8 143.5h1.2zM3 142.1v.3zM2.7 141.8l.3 .3zM293.7 143.3l1.2-1.1zM294 141.6l-.3 .3zM294 141.6h.6zM293.7 143.3h1.2z"/>
<path d="M294.9 141.9v.3zM294.6 141.6l.3 .3zM1.2 162.8v41zM1.2 162.8h2.4zM3.6 162.8v38.6zM293.1 124.2v38.6zM293.1 162.8h2.4zM295.5 124.2v38.6zM2 182.3l.6-.6zM2 183.5h1.2zM2.6 181.7v1.8zM234.7 193.7h58.4z"/>
<path d="M234.7 189.8h58.4zM236.6 195.4l.6-.5zM236.6 196.5h1.1zM237.2 194.9v1.6zM238.2 194.9h1.1zM238.2 196.3v.2zM239.3 194.9v.3zM238.2 196.3l1.1-1.1zM241.4 194.9v1.6zM241.4 194.9l1.1 1.6zM242.5 194.9v1.6zM243 195.7v.6z"/>
<path d="M243 196.3l.3 .2zM243.3 196.5h.5zM243.3 195.4l-.3 .3zM243.8 187.2v1.8zM243.8 189h.9zM244.1 196.3l-.3 .2zM243.3 195.4h.5zM244.1 195.7v.6zM243.8 195.4l.3 .3zM244.6 195.4l.6 1.1zM244.7 189l.3-.3zM243.8 187.8h.9z"/>
<path d="M245 188.1v.6zM244.7 187.8l.3 .3zM245.7 195.4l-.5 1.1zM245.6 187.8v.9zM245.6 188.7l.2 .3zM245.8 189h.9zM246.7 187.8v1.2zM247.3 189h.9zM247.3 188.1l.3-.3zM247.3 188.1l.3 .3zM247.6 187.8h.9zM248.9 195.4l-1.1 1.1z"/>
<path d="M248.1 194.9l-.3 .3zM248.2 189l.3-.3zM247.6 188.4h.6zM248.2 188.4l.3 .3zM248.1 194.9h.5zM247.8 196.5h1.1zM248.9 195.2v.2zM248.6 194.9l.3 .3zM249.1 188.1h1.2zM249.4 195.2v1.1zM249.4 195.2l.3-.3zM249.4 196.3l1.1-1.1z"/>
<path d="M249.7 194.9h.5zM249.4 196.3l.3 .2zM250.2 194.9l.3 .3zM249.7 196.5h.5zM250.5 195.2v1.1zM250.5 196.3l-.3 .2zM250.9 187.8v.9zM250.9 188.7l.3 .3zM251 195.4l.6-.5zM251 196.5h1.1zM251.2 189l.3-.3zM251.5 188.7l.3 .3z"/>
<path d="M251.6 194.9v1.6zM251.8 189l.3-.3zM252.1 187.8v.9zM252.6 195.4l.6-.5zM252.6 196.5h1.1zM252.7 187.8h.3zM252.7 189h.6zM253 187.8v1.2zM253 186.9v.3zM253.2 194.9v1.6zM253.8 187.8v1.2zM253.8 188.4l.6-.6z"/>
<path d="M254.4 187.8h.3zM255.3 187.8h.3zM255.3 189h.6zM255.6 187.8v1.2zM255.6 186.9v.3zM255.8 195.2v1.1zM256.1 194.9l-.3 .3zM255.8 196.3l1.1-1.1zM256.1 194.9h.5zM255.8 196.3l.3 .2zM256.5 187.8v1.2zM256.5 187.8h.9z"/>
<path d="M256.6 194.9l.3 .3zM256.1 196.5h.5zM256.9 195.2v1.1zM256.6 196.5l.3-.2zM257.4 187.8l.3 .3zM257.4 195.2l.3-.3zM257.7 188.1v.9zM257.7 194.9h.5zM257.4 196.3l.3 .2zM258.2 194.9l.3 .3zM258 195.7h.2zM258.2 195.7l.3 .3z"/>
<path d="M257.7 196.5h.5zM258.3 188.1v.6zM258.3 188.7l.3 .3zM258.5 195.2v.2zM258.2 195.7l.3-.3zM258.5 196v.3zM258.5 196.3l-.3 .2zM258.6 187.8l-.3 .3zM258.6 189h.9zM258.9 189.6h.3zM259 195.4h.3zM259 195.4v.3z"/>
<path d="M259 196.3h.3zM259 196.3v.2zM259.2 189.6l.3-.3zM259.3 195.4v.3zM259 195.7h.3zM259.3 196.3v.2zM259 196.5h.3zM259.5 187.8v1.5zM258.6 187.8h.9zM259.8 194.9v.8zM259.8 195.7l.6-.3zM259.8 196.3l.3 .2z"/>
<path d="M260.4 195.4h.2zM260.6 195.4l.3 .3zM260.1 196.5h.5zM259.8 194.9h1.1zM260.9 195.7v.6zM260.9 196.3l-.3 .2zM261.4 196.3l.3 .2zM261.4 195.2v.2zM261.4 195.4l.3 .3zM261.7 196.5h.5zM261.7 194.9l-.3 .3zM261.7 195.7h.8z"/>
<path d="M262.5 196.3l-.3 .2zM261.7 194.9h.5zM262.5 195.2v1.1zM262.2 194.9l.3 .3zM263 195.4h.3zM263 195.4v.3zM263 196.3h.3zM263 196.3v.2zM263.3 195.4v.3zM263 195.7h.3zM263.3 196.3v.2zM263 196.5h.3z"/>
<path d="M263.8 195.2v1.1zM263.8 195.2l.3-.3zM263.8 196.3l1.1-1.1zM264.1 194.9h.5zM263.8 196.3l.3 .2zM264.6 194.9l.3 .3zM264.1 196.5h.5zM264.9 195.2v1.1zM264.9 196.3l-.3 .2zM265.4 194.9v.8zM265.4 195.7l.6-.3zM265.4 196.3l.3 .2z"/>
<path d="M266 195.4h.2zM266.2 195.4l.3 .3zM265.7 196.5h.5zM265.4 194.9h1.1zM266.5 195.7v.6zM266.5 196.3l-.3 .2zM279.6 197.6h13.5zM234.7 197.6h44.9zM281.1 199.2l.6-.6zM281.7 198.6v1.8zM284.7 199.2l.6-.6zM285.3 198.6v1.8z"/>
<path d="M293.1 193.7v3.9zM293.1 189.8v3.9zM293.1 186v3.8zM293.1 162.8v23.2zM293.9 180.8l.6-.6zM293.9 181.9h1.2zM294.5 180.2v1.7zM1.2 203.8h38.6zM3.6 201.4h36.2zM19.8 202.4v1.2zM19.8 202.4l.6-.6zM19.8 202.7h1.2z"/>
<path d="M20.4 201.8l.6 .6zM21 202.4v1.2zM39.8 203.8h36.2zM39.8 201.4h36.2zM39.8 201.4v2.4zM57.8 201.8v1.8zM57.8 201.8h.9zM57.8 202.7h.9zM58.7 201.8l.3 .3zM58.7 202.7l.3 .3zM57.8 203.6h.9zM59 202.1v.3z"/>
<path d="M59 202.4l-.3 .3zM59 203v.3zM59 203.3l-.3 .3zM76 203.8h36.2zM76 201.4h36.2zM76 201.4v2.4zM93.3 202.1v1.2zM93.3 203.3l.3 .3zM93.6 201.8l-.3 .3zM93.6 203.6h.6zM93.6 201.8h.6zM94.2 203.6l.3-.3z"/>
<path d="M94.2 201.8l.3 .3zM112.2 203.8h36.2zM112.2 201.4h36.2zM112.2 201.4v2.4zM130 201.8v1.8zM130 203.6h.9zM130.9 203.6l.3-.3zM130 201.8h.9zM131.2 202.1v1.2zM130.9 201.8l.3 .3zM148.4 203.8h36.1zM148.4 201.4h36.1z"/>
<path d="M148.4 201.4v2.4zM166.1 201.8v1.8zM166.1 203.6h1.2zM166.1 202.7h.6zM166.1 201.8h1.2zM184.5 203.8h36.2zM184.5 201.4h36.2zM184.5 201.4v2.4zM201.6 201.8v1.8zM201.6 201.8h1.2zM201.6 202.7h.6zM220.7 203.8h36.2z"/>
<path d="M220.7 201.4h14zM220.7 201.4v2.4zM234.7 201.4h44.9zM237.3 202.1v1.2zM237.3 203.3l.3 .3zM237.6 201.8l-.3 .3zM237.6 203.6h.6zM237.6 201.8h.6zM238.2 203.6l.3-.3zM238.2 201.8l.3 .3zM238.5 202.7v.6zM237.9 202.7h.6z"/>
<path d="M256.9 203.8h38.6zM234.7 201.4h22.2zM256.9 201.4v2.4zM275.5 201.8v1.8zM275.5 202.7h1.2zM276.7 201.8v1.8zM279.6 201.4h13.5zM279.6 197.6v3.8zM281.1 200.4h1.2zM284.1 198.6l-1.2 1.8zM284.7 200.4h1.2zM293.1 197.6v3.8z"/>
<path d="M295.5 162.8v41z"/>
</g>
<g fill="#000" stroke="#000" stroke-width=".47">
<path d="M45.6 78.4h.9zM45.6 76.5h.9zM45.6 74.5h.9zM45.6 72.6h.9zM45.6 70.7h.9zM45.6 68.7h.9zM45.6 66.8h.9zM45.6 64.9h.9zM86.1 78.4h1zM86.1 76.5h1zM86.1 74.5h1zM86.1 72.6h1z"/>
<path d="M86.1 70.7h1zM86.1 68.7h1zM86.1 66.8h1zM86.1 64.9h1zM126.6 78.4h1zM126.6 76.5h1zM126.6 74.5h1zM126.6 72.6h1zM126.6 70.7h1zM126.6 68.7h1zM126.6 66.8h1zM126.6 64.9h1z"/>
<path d="M196.1 78.4h1zM196.1 76.5h1zM196.1 74.5h1zM196.1 72.6h1zM196.1 70.7h1zM196.1 68.7h1zM196.1 66.8h1zM196.1 64.9h1zM236.7 78.4h.9zM236.7 76.5h.9zM236.7 74.5h.9zM236.7 72.6h.9z"/>
<path d="M236.7 70.7h.9zM236.7 68.7h.9zM236.7 66.8h.9zM236.7 64.9h.9zM277.2 78.4h1zM277.2 76.5h1zM277.2 74.5h1zM277.2 72.6h1zM277.2 70.7h1zM277.2 68.7h1zM277.2 66.8h1zM277.2 64.9h1z"/>
<path d="M45.6 99.6h.9zM45.6 97.7h.9zM45.6 95.8h.9zM45.6 93.8h.9zM45.6 91.9h.9zM45.6 90h.9zM45.6 88h.9zM45.6 86.1h.9zM45.6 84.2h.9zM45.6 82.3h.9zM45.6 80.3h.9zM86.1 99.6h1z"/>
<path d="M86.1 97.7h1zM86.1 95.8h1zM86.1 93.8h1zM86.1 91.9h1zM86.1 90h1zM86.1 88h1zM86.1 86.1h1zM86.1 84.2h1zM86.1 82.3h1zM86.1 80.3h1zM126.6 99.6h1zM126.6 97.7h1z"/>
<path d="M126.6 95.8h1zM126.6 93.8h1zM126.6 91.9h1zM126.6 90h1zM126.6 88h1zM126.6 86.1h1zM126.6 84.2h1zM126.6 82.3h1zM126.6 80.3h1zM196.1 99.6h1zM196.1 97.7h1zM196.1 95.8h1z"/>
<path d="M196.1 93.8h1zM196.1 91.9h1zM196.1 90h1zM196.1 88h1zM196.1 86.1h1zM196.1 84.2h1zM196.1 82.3h1zM196.1 80.3h1zM236.7 99.6h.9zM236.7 97.7h.9zM236.7 95.8h.9zM236.7 93.8h.9z"/>
<path d="M236.7 91.9h.9zM236.7 90h.9zM236.7 88h.9zM236.7 86.1h.9zM236.7 84.2h.9zM236.7 82.3h.9zM236.7 80.3h.9zM277.2 99.6h1zM277.2 97.7h1zM277.2 95.8h1zM277.2 93.8h1zM277.2 91.9h1z"/>
<path d="M277.2 90h1zM277.2 88h1zM277.2 86.1h1zM277.2 84.2h1zM277.2 82.3h1zM277.2 80.3h1zM45.6 118.9h.9zM45.6 117h.9zM45.6 115.1h.9zM45.6 113.1h.9zM45.6 111.2h.9zM45.6 109.3h.9z"/>
<path d="M45.6 107.3h.9zM45.6 105.4h.9zM45.6 103.5h.9zM45.6 101.6h.9zM86.1 118.9h1zM86.1 117h1zM86.1 115.1h1zM86.1 113.1h1zM86.1 111.2h1zM86.1 109.3h1zM86.1 107.3h1zM86.1 105.4h1z"/>
<path d="M86.1 103.5h1zM86.1 101.6h1zM126.6 118.9h1zM126.6 117h1zM126.6 115.1h1zM126.6 113.1h1zM126.6 111.2h1zM126.6 109.3h1zM126.6 107.3h1zM126.6 105.4h1zM126.6 103.5h1zM126.6 101.6h1z"/>
<path d="M196.1 118.9h1zM196.1 117h1zM196.1 115.1h1zM196.1 113.1h1zM196.1 111.2h1zM196.1 109.3h1zM196.1 107.3h1zM196.1 105.4h1zM196.1 103.5h1zM196.1 101.6h1zM236.7 118.9h.9zM236.7 117h.9z"/>
<path d="M236.7 115.1h.9zM236.7 113.1h.9zM236.7 111.2h.9zM236.7 109.3h.9zM236.7 107.3h.9zM236.7 105.4h.9zM236.7 103.5h.9zM236.7 101.6h.9zM277.2 118.9h1zM277.2 117h1zM277.2 115.1h1zM277.2 113.1h1z"/>
<path d="M277.2 111.2h1zM277.2 109.3h1zM277.2 107.3h1zM277.2 105.4h1zM277.2 103.5h1zM277.2 101.6h1zM45.6 124.7h.9zM45.6 122.8h.9zM45.6 120.8h.9zM86.1 124.7h1zM86.1 122.8h1zM86.1 120.8h1z"/>
<path d="M126.6 124.7h1zM126.6 122.8h1zM126.6 120.8h1zM196.1 124.7h1zM196.1 122.8h1zM196.1 120.8h1zM236.7 124.7h.9zM236.7 122.8h.9zM236.7 120.8h.9zM277.2 124.7h1zM277.2 122.8h1zM277.2 120.8h1z"/>
<path d="M220.7 186h14zM234.7 186h58.4zM234.7 197.6v3.8zM234.7 193.7v3.9zM234.7 189.8v3.9zM234.7 186v3.8zM220.7 186v15.4z"/>
</g>
<g fill="#000" stroke="#000" stroke-width=".32">
<path d="M48.5 62.9v63.7zM44.6 62.9h3.9zM89 62.9v63.7zM85.2 62.9h3.8zM129.5 62.9v63.7zM125.7 62.9h3.8zM199 62.9v63.7zM195.2 62.9h3.8zM239.6 62.9v63.7zM235.7 62.9h3.9zM280.1 62.9v63.7zM276.2 62.9h3.9z"/>
<path d="M44.6 126.6h3.9zM44.6 62.9v63.7zM85.2 126.6h3.8zM85.2 62.9v63.7zM125.7 126.6h3.8zM125.7 62.9v63.7zM195.2 126.6h3.8zM195.2 62.9v63.7zM235.7 126.6h3.9zM235.7 62.9v63.7zM276.2 126.6h3.9zM276.2 62.9v63.7z"/>
</g>
<use href="#words"/>
</svg>
